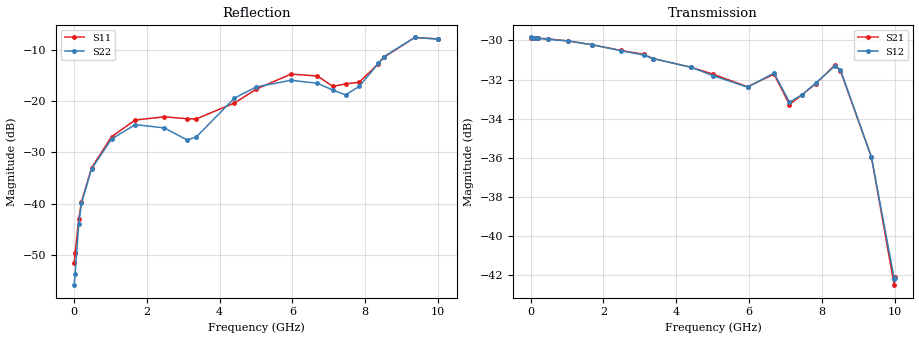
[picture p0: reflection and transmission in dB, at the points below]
! Device ID: PE43704
! Dir: z:\PE43704\PE43704_Char_1_20130516\PE43704\AMB\3p400V\29p00dB
! Serial: 14
! Insertion: A
! Impedance: 50 ohm
! Temp: Amb
! VDD: 3.400V
! Attenuation Step: 29.00dB
! IDD: 1.139219e-01mA
#  Hz  S  RI  R  50
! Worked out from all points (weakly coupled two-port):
!   401 points, 10 MHz to 10.01 GHz, reference 50 ohm
!   highest |S21| = -29.86 dB at 35 MHz (marker M1); lowest = -42.5 dB at 9.985 GHz (marker M2)
!   lowest |S11| = -51.5 dB at 10 MHz (marker M3), VSWR 1.01, Z = 50.3 + j0.05 ohm
!   |S11| at or under -10 dB: start of sweep to 8.725 GHz
!   |S22| runs from -55.8 to -7.6 dB; largest |S21 - S12| = 0.00066
!   S11 on the Smith chart (normalised r, x): 10 MHz: 1.01, +0.00; 7.46 GHz: 0.79, +0.15; 8.51 GHz: 0.81, +0.46; 9.36 GHz: 0.54, +0.49; 10.01 GHz: 0.47, +0.28
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1e7  0.0026 0.000497  0.0321 -9.45e-05  0.0322 -3.77e-05  -0.00156 0.000423
3.5e7  0.00276 0.0018  0.0321 -0.000288  0.0321 -0.000335  -0.00132 0.0016
1.35e8  0.00248 0.00666  0.0321 -0.00112  0.0321 -0.00108  -0.00158 0.00619
2.1e8  0.00131 0.0104  0.032 -0.00167  0.032 -0.00164  -0.00255 0.00978
4.85e8  -0.00581 0.0215  0.0317 -0.00369  0.0316 -0.00375  -0.00948 0.0196
1.035e9  -0.0333 0.0301  0.0306 -0.00759  0.0306 -0.00763  -0.0344 0.0251
1.685e9  -0.0632 0.0162  0.0285 -0.0118  0.0285 -0.0118  -0.0583 0.00821
2.485e9  -0.0699 -0.00535  0.0251 -0.0161  0.0251 -0.016  -0.0542 -0.0072
3.11e9  -0.067 -0.00531  0.0221 -0.019  0.0221 -0.0188  -0.0416 0.00341
3.36e9  -0.0669 0.000651  0.0206 -0.0196  0.0206 -0.0196  -0.0429 0.0121
4.41e9  -0.0841 0.0453  0.0158 -0.0219  0.0158 -0.0219  -0.0902 0.057
5.01e9  -0.1076 0.0737  0.0134 -0.0222  0.0133 -0.022  -0.1228 0.061
5.96e9  -0.1546 0.0971  0.00881 -0.0224  0.00893 -0.0223  -0.1485 0.057
6.685e9  -0.1541 0.0832  0.00691 -0.025  0.00682 -0.0252  -0.1383 0.0544
7.11e9  -0.123 0.0643  0.00197 -0.0216  0.002 -0.0219  -0.1066 0.0704
7.46e9  -0.1124 0.0939  0.00291 -0.0228  0.00296 -0.0228  -0.0775 0.0843
7.835e9  -0.0656 0.1374  0.0026 -0.0244  0.00252 -0.0245  -0.0612 0.1244
8.36e9  -0.0333 0.2283  -0.00556 -0.0268  -0.00534 -0.0267  -0.0775 0.2185
8.51e9  -0.0361 0.2632  -0.00797 -0.0252  -0.00789 -0.0254  -0.0905 0.2541
9.36e9  -0.1785 0.3743  -0.0113 -0.0112  -0.0114 -0.0111  -0.2423 0.3376
9.985e9  -0.3083 0.2584  -0.00164 -0.00731  -0.00202 -0.00752  -0.3546 0.1832
1.001e10  -0.3132 0.2497  -0.00163 -0.0077  -0.00132 -0.00768  -0.3583 0.1747
